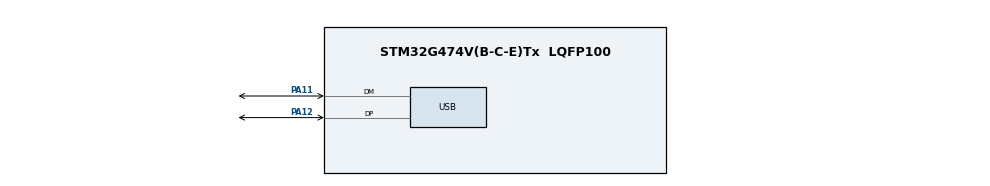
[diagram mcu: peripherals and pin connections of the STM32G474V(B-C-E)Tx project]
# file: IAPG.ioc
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Mcu.Family=STM32G4
Mcu.Name=STM32G474V(B-C-E)Tx
Mcu.Package=LQFP100
NVIC.PriorityGroup=NVIC_PRIORITYGROUP_4
NVIC.USB_LP_IRQn=true\:0\:0\:false\:false\:true\:false\:true\:true
PA11.Mode=Device
PA11.Signal=USB_DM
PA12.Mode=Device
PA12.Signal=USB_DP
PC14-OSC32_IN.Mode=LSE-External-Oscillator
PC14-OSC32_IN.Signal=RCC_OSC32_IN
PC15-OSC32_OUT.Mode=LSE-External-Oscillator
PC15-OSC32_OUT.Signal=RCC_OSC32_OUT
ProjectManager.HeapSize=0x200
ProjectManager.StackSize=0x400
ProjectManager.TargetToolchain=STM32CubeIDE
RCC.AHBFreq_Value=16000000
RCC.APB1Freq_Value=16000000
RCC.APB1TimFreq_Value=16000000
RCC.APB2Freq_Value=16000000
RCC.APB2TimFreq_Value=16000000
RCC.CortexFreq_Value=16000000
RCC.EXTERNAL_CLOCK_VALUE=12288000
RCC.HCLKFreq_Value=16000000
RCC.HSE_VALUE=8000000
RCC.HSI48_VALUE=48000000
RCC.HSI_VALUE=16000000
RCC.PLLN=12
RCC.PLLQ=RCC_PLLQ_DIV4
RCC.SYSCLKFreq_VALUE=16000000
RCC.USBFreq_Value=48000000
RCC.VCOOutputFreq_Value=192000000
USB_DEVICE.CLASS_NAME_FS=CDC
USB_DEVICE.MANUFACTURER_STRING=Lebois Racing
USB_DEVICE.PRODUCT_STRING_CDC_FS=Competition Control Box V3
USB_DEVICE.VirtualMode=Cdc
USB_DEVICE.VirtualModeFS=Cdc_FS
VP_SYS_VS_DBSignals.Mode=DisableDeadBatterySignals
VP_USB_DEVICE_VS_USB_DEVICE_CDC_FS.Mode=CDC_FS
board=custom

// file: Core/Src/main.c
/* USER CODE BEGIN Header */
/**
  ******************************************************************************
  * @file           : main.c
  * @brief          : Main program body
  ******************************************************************************
  * @attention
  *
  * Copyright (c) 2026 STMicroelectronics.
  * All rights reserved.
  *
  * This software is licensed under terms that can be found in the LICENSE file
  * in the root directory of this software component.
  * If no LICENSE file comes with this software, it is provided AS-IS.
  *
  ******************************************************************************
  */
/* USER CODE END Header */
#include "main.h"
#include "usb_device.h"

/* USER CODE BEGIN Includes */
#include "bootloader.h"
/* USER CODE END Includes */

void SystemClock_Config(void);
static void MX_GPIO_Init(void);

int main(void)
{

  /* USER CODE BEGIN 1 */
  /* Tres tot : si l'app est valide et qu'aucun ordre DFU n'est present, on y
     saute directement ; sinon on reste dans le bootloader (USB CDC). */
  BL_Init();
  /* USER CODE END 1 */

  /* MCU Configuration--------------------------------------------------------*/

  /* Reset of all peripherals, Initializes the Flash interface and the Systick. */
  HAL_Init();

  /* Configure the system clock */
  SystemClock_Config();

  /* Initialize all configured peripherals */
  MX_GPIO_Init();
  MX_USB_Device_Init();

  /* Infinite loop */
  while (1)
  {
    BL_Process();
  }
}

void SystemClock_Config(void)
{
  RCC_OscInitTypeDef RCC_OscInitStruct = {0};
  RCC_ClkInitTypeDef RCC_ClkInitStruct = {0};

  /** Configure the main internal regulator output voltage
  */
  HAL_PWREx_ControlVoltageScaling(PWR_REGULATOR_VOLTAGE_SCALE1);

  /** Initializes the RCC Oscillators according to the specified parameters
  * in the RCC_OscInitTypeDef structure.
  */
  RCC_OscInitStruct.OscillatorType = RCC_OSCILLATORTYPE_HSI|RCC_OSCILLATORTYPE_HSI48;
  RCC_OscInitStruct.HSIState = RCC_HSI_ON;
  RCC_OscInitStruct.HSI48State = RCC_HSI48_ON;
  RCC_OscInitStruct.HSICalibrationValue = RCC_HSICALIBRATION_DEFAULT;
  RCC_OscInitStruct.PLL.PLLState = RCC_PLL_ON;
  RCC_OscInitStruct.PLL.PLLSource = RCC_PLLSOURCE_HSI;
  RCC_OscInitStruct.PLL.PLLM = RCC_PLLM_DIV1;
  RCC_OscInitStruct.PLL.PLLN = 12;
  RCC_OscInitStruct.PLL.PLLP = RCC_PLLP_DIV2;
  RCC_OscInitStruct.PLL.PLLQ = RCC_PLLQ_DIV4;
  RCC_OscInitStruct.PLL.PLLR = RCC_PLLR_DIV2;
  if (HAL_RCC_OscConfig(&RCC_OscInitStruct) != HAL_OK)
  {
    Error_Handler();
  }

  /** Initializes the CPU, AHB and APB buses clocks
  */
  RCC_ClkInitStruct.ClockType = RCC_CLOCKTYPE_HCLK|RCC_CLOCKTYPE_SYSCLK
                              |RCC_CLOCKTYPE_PCLK1|RCC_CLOCKTYPE_PCLK2;
  RCC_ClkInitStruct.SYSCLKSource = RCC_SYSCLKSOURCE_PLLCLK;   /* PLLR = 96 MHz (HSI) : USB IT servi a temps */
  RCC_ClkInitStruct.AHBCLKDivider = RCC_SYSCLK_DIV1;
  RCC_ClkInitStruct.APB1CLKDivider = RCC_HCLK_DIV1;
  RCC_ClkInitStruct.APB2CLKDivider = RCC_HCLK_DIV1;

  if (HAL_RCC_ClockConfig(&RCC_ClkInitStruct, FLASH_LATENCY_4) != HAL_OK)
  {
    Error_Handler();
  }
}

static void MX_GPIO_Init(void)
{

  /* GPIO Ports Clock Enable */
  __HAL_RCC_GPIOC_CLK_ENABLE();
  __HAL_RCC_GPIOA_CLK_ENABLE();

}

void Error_Handler(void)
{
  __disable_irq();
  while (1)
  {
  }
}
